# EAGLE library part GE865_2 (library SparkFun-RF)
Telit quad cell module (CEL-09720)

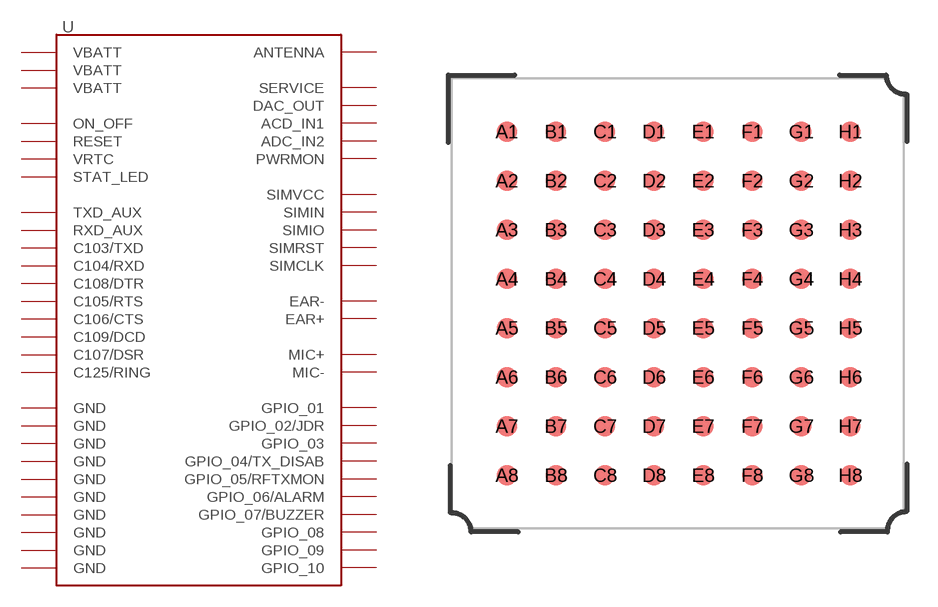
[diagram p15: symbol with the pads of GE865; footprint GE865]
Designator prefix -

## GE865_2  [GE865]
A1  C105/RTS
A2  C106/CTS
A3  C103/TXD
A4  C104/RXD
A5  SIMCLK
A6  SIMIO
A7  SIMVCC
A8  SIMRST
B1  ON_OFF
B2  C107/DSR
B3  C108/DTR
B4  C125/RING
B5  C109/DCD
B7  SIMIN
B8  MIC+
C1  RESET
C2  GND
C7  GND
C8  MIC-
D1  TXD_AUX
D2  GPIO_02/JDR
D3  GPIO_01
D4  GPIO_08
D8  EAR+
E1  RXD_AUX
E2  PWRMON
E3  GPIO_10
E4  GPIO_03
E5  GND
E7  GND
E8  EAR-
F1  VBATT
F2  VBATT
F3  VBATT
F4  GPIO_09
F5  ACD_IN1
F6  ADC_IN2
G1  GND
G2  GPIO_05/RFTXMON
G3  GND
G4  GND
G5  GND
G6  GPIO_07/BUZZER
G7  DAC_OUT
G8  STAT_LED
H1  SERVICE
H2  VRTC
H3  GND
H5  ANTENNA
H6  GND
H7  GPIO_04/TX_DISAB
H8  GPIO_06/ALARM

## Footprint GE865 (pad centres in mm)
smd 1 x 1: A1 -8.4,8.4; A2 -8.4,6; A3 -8.4,3.6; A4 -8.4,1.2; A5 -8.4,-1.2; A6 -8.4,-3.6; A7 -8.4,-6; A8 -8.4,-8.4; B1 -6,8.4; B2 -6,6; B3 -6,3.6; B4 -6,1.2; B5 -6,-1.2; B6 -6,-3.6; B7 -6,-6; B8 -6,-8.4; C1 -3.6,8.4; C2 -3.6,6; C3 -3.6,3.6; C4 -3.6,1.2; C5 -3.6,-1.2; C6 -3.6,-3.6; C7 -3.6,-6; C8 -3.6,-8.4; D1 -1.2,8.4; D2 -1.2,6; D3 -1.2,3.6; D4 -1.2,1.2; D5 -1.2,-1.2; D6 -1.2,-3.6; D7 -1.2,-6; D8 -1.2,-8.4; E1 1.2,8.4; E2 1.2,6; E3 1.2,3.6; E4 1.2,1.2; E5 1.2,-1.2; E6 1.2,-3.6; E7 1.2,-6; E8 1.2,-8.4; F1 3.6,8.4; F2 3.6,6; F3 3.6,3.6; F4 3.6,1.2; F5 3.6,-1.2; F6 3.6,-3.6; F7 3.6,-6; F8 3.6,-8.4; G1 6,8.4; G2 6,6; G3 6,3.6; G4 6,1.2; G5 6,-1.2; G6 6,-3.6; G7 6,-6; G8 6,-8.4; H1 8.4,8.4; H2 8.4,6; H3 8.4,3.6; H4 8.4,1.2; H5 8.4,-1.2; H6 8.4,-3.6; H7 8.4,-6; H8 8.4,-8.4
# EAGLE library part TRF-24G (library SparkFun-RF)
2.4GHz wireless module

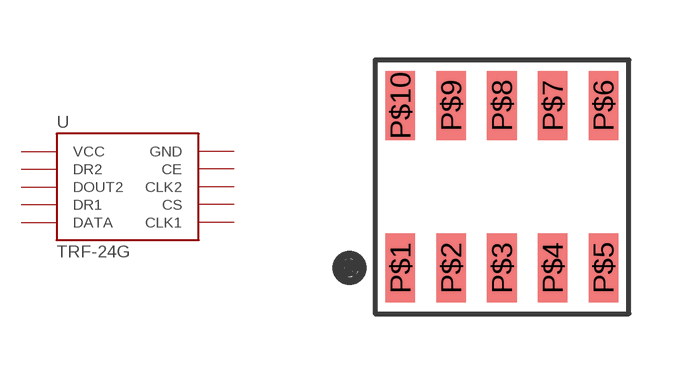
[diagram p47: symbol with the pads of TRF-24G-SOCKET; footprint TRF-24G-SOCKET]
Designator prefix -

## TRF-24G  [TRF-24G-SOCKET]
P$1  VCC
P$2  DR2
P$3  DOUT2
P$4  DR1
P$5  DATA
P$6  CLK1
P$7  CS
P$8  CLK2
P$9  CE
P$10  GND

## Footprint TRF-24G-SOCKET (pad centres in mm)
smd 0.74 x 1.727: P$1 0,0; P$2 1.27,0; P$3 2.54,0; P$4 3.81,0; P$5 5.08,0; P$6 5.08,4.064; P$7 3.81,4.064; P$8 2.54,4.064; P$9 1.27,4.064; P$10 0,4.064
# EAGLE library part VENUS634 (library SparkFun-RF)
Venus634 from SkyTraq

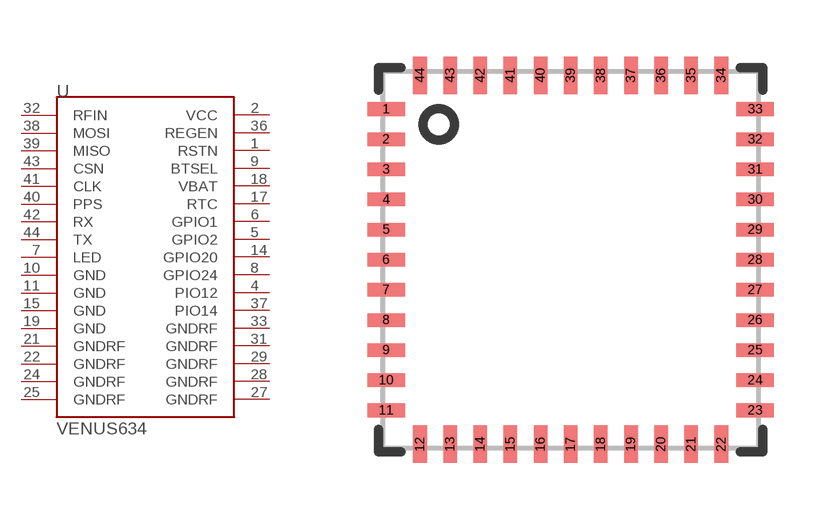
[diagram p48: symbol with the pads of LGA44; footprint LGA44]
Designator prefix -

## VENUS634SMD (PROD_ID: IC-12645)  [LGA44]
1  RSTN
2  VCC
4  PIO12
5  GPIO2
6  GPIO1
7  LED
8  GPIO24
9  BTSEL
10  GND
11  GND
14  GPIO20
15  GND
17  RTC
18  VBAT
19  GND
21  GNDRF
22  GNDRF
24  GNDRF
25  GNDRF
27  GNDRF
28  GNDRF
29  GNDRF
31  GNDRF
32  RFIN
33  GNDRF
36  REGEN
37  PIO14
38  MOSI
39  MISO
40  PPS
41  CLK
42  RX
43  CSN
44  TX

## Footprint LGA44 (pad centres in mm)
LGA44 - Used for Venus GPS
smd 1 x 0.36: 1 -4.9,4; 2 -4.9,3.2; 3 -4.9,2.4; 4 -4.9,1.6; 5 -4.9,0.8; 6 -4.9,0; 7 -4.9,-0.8; 8 -4.9,-1.6; 9 -4.9,-2.4; 10 -4.9,-3.2; 11 -4.9,-4; 23 4.9,-4; 24 4.9,-3.2; 25 4.9,-2.4; 26 4.9,-1.6; 27 4.9,-0.8; 28 4.9,0; 29 4.9,0.8; 30 4.9,1.6; 31 4.9,2.4; 32 4.9,3.2; 33 4.9,4
smd 0.36 x 1: 12 -4,-4.9; 13 -3.2,-4.9; 14 -2.4,-4.9; 15 -1.6,-4.9; 16 -0.8,-4.9; 17 0,-4.9; 18 0.8,-4.9; 19 1.6,-4.9; 20 2.4,-4.9; 21 3.2,-4.9; 22 4,-4.9; 34 4,4.9; 35 3.2,4.9; 36 2.4,4.9; 37 1.6,4.9; 38 0.8,4.9; 39 0,4.9; 40 -0.8,4.9; 41 -1.6,4.9; 42 -2.4,4.9; 43 -3.2,4.9; 44 -4,4.9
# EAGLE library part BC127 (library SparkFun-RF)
Blue Creations BC127 BLE module Hyper-competent Bluetooth 4.0 module, with: - Pre-4.0 support - 4 Cap sense inputs - 1 Analog input - 8 GPIO - 3 Open-drain LED drivers - Onboard battery charge circuitry - SPP/UART support - PCM Audio support - SPI port - Built-in USB - All kinds of other crazy crap

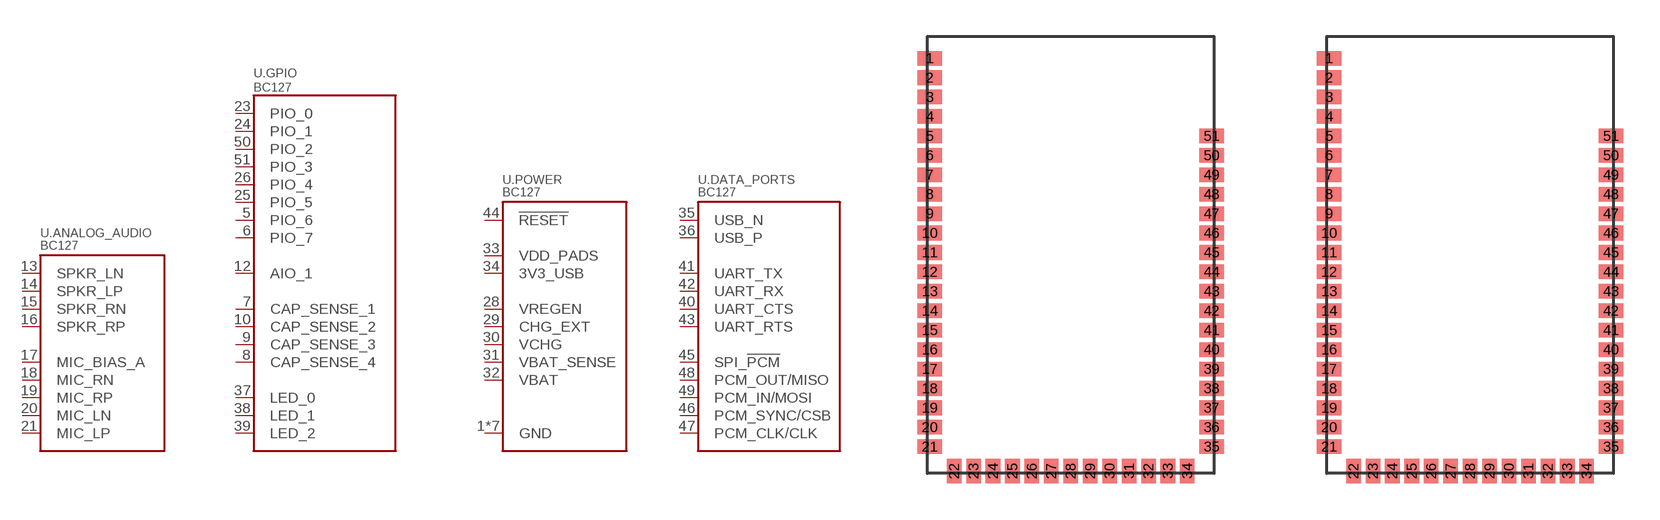
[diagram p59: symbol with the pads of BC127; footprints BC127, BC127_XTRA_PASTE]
Designator prefix U; gates .ANALOG_AUDIO=BC127_ANALOG_AUDIO .GPIO=BC127_GPIO .POWER=BC127_POWER .DATA_PORTS=BC127_DATA_PORTS

## BC127 (VALUE: BC127)  [BC127]
1  .POWER:GND
2  .POWER:GND
3  .POWER:GND
4  .POWER:GND
5  .GPIO:PIO_6
6  .GPIO:PIO_7
7  .GPIO:CAP_SENSE_1
8  .GPIO:CAP_SENSE_4
9  .GPIO:CAP_SENSE_3
10  .GPIO:CAP_SENSE_2
11  .POWER:GND
12  .GPIO:AIO_1
13  .ANALOG_AUDIO:SPKR_LN
14  .ANALOG_AUDIO:SPKR_LP
15  .ANALOG_AUDIO:SPKR_RN
16  .ANALOG_AUDIO:SPKR_RP
17  .ANALOG_AUDIO:MIC_BIAS_A
18  .ANALOG_AUDIO:MIC_RN
19  .ANALOG_AUDIO:MIC_RP
20  .ANALOG_AUDIO:MIC_LN
21  .ANALOG_AUDIO:MIC_LP
22  .POWER:GND
23  .GPIO:PIO_0
24  .GPIO:PIO_1
25  .GPIO:PIO_5
26  .GPIO:PIO_4
27  .POWER:GND
28  .POWER:VREGEN
29  .POWER:CHG_EXT
30  .POWER:VCHG
31  .POWER:VBAT_SENSE
32  .POWER:VBAT
33  .POWER:VDD_PADS
34  .POWER:3V3_USB
35  .DATA_PORTS:USB_N
36  .DATA_PORTS:USB_P
37  .GPIO:LED_0
38  .GPIO:LED_1
39  .GPIO:LED_2
40  .DATA_PORTS:UART_CTS
41  .DATA_PORTS:UART_TX
42  .DATA_PORTS:UART_RX
43  .DATA_PORTS:UART_RTS
44  .POWER:!RESET
45  .DATA_PORTS:SPI_!PCM
46  .DATA_PORTS:PCM_SYNC/CSB
47  .DATA_PORTS:PCM_CLK/CLK
48  .DATA_PORTS:PCM_OUT/MISO
49  .DATA_PORTS:PCM_IN/MOSI
50  .GPIO:PIO_2
51  .GPIO:PIO_3

## BC127EXTRA_PASTE  [BC127_XTRA_PASTE]
Pads as for BC127

## Footprint BC127 (pad centres in mm)
smd 1 x 0.6: 1 -5.8,8.1; 2 -5.8,7.3; 3 -5.8,6.5; 4 -5.8,5.7; 5 -5.8,4.9; 6 -5.8,4.1; 7 -5.8,3.3; 8 -5.8,2.5; 9 -5.8,1.7; 10 -5.8,0.9; 11 -5.8,0.1; 12 -5.8,-0.7; 13 -5.8,-1.5; 14 -5.8,-2.3; 15 -5.8,-3.1; 16 -5.8,-3.9; 17 -5.8,-4.7; 18 -5.8,-5.5; 19 -5.8,-6.3; 20 -5.8,-7.1; 21 -5.8,-7.9; 35 5.8,-7.9; 36 5.8,-7.1; 37 5.8,-6.3; 38 5.8,-5.5; 39 5.8,-4.7; 40 5.8,-3.9; 41 5.8,-3.1; 42 5.8,-2.3; 43 5.8,-1.5; 44 5.8,-0.7; 45 5.8,0.1; 46 5.8,0.9; 47 5.8,1.7; 48 5.8,2.5; 49 5.8,3.3; 50 5.8,4.1; 51 5.8,4.9
smd 0.6 x 1: 22 -4.8,-8.9; 23 -4,-8.9; 24 -3.2,-8.9; 25 -2.4,-8.9; 26 -1.6,-8.9; 27 -0.8,-8.9; 28 0,-8.9; 29 0.8,-8.9; 30 1.6,-8.9; 31 2.4,-8.9; 32 3.2,-8.9; 33 4,-8.9; 34 4.8,-8.9

## Footprint BC127_XTRA_PASTE (pad centres in mm)
smd 1 x 0.6: 1 -5.8,8.1; 2 -5.8,7.3; 3 -5.8,6.5; 4 -5.8,5.7; 5 -5.8,4.9; 6 -5.8,4.1; 7 -5.8,3.3; 8 -5.8,2.5; 9 -5.8,1.7; 10 -5.8,0.9; 11 -5.8,0.1; 12 -5.8,-0.7; 13 -5.8,-1.5; 14 -5.8,-2.3; 15 -5.8,-3.1; 16 -5.8,-3.9; 17 -5.8,-4.7; 18 -5.8,-5.5; 19 -5.8,-6.3; 20 -5.8,-7.1; 21 -5.8,-7.9; 35 5.8,-7.9; 36 5.8,-7.1; 37 5.8,-6.3; 38 5.8,-5.5; 39 5.8,-4.7; 40 5.8,-3.9; 41 5.8,-3.1; 42 5.8,-2.3; 43 5.8,-1.5; 44 5.8,-0.7; 45 5.8,0.1; 46 5.8,0.9; 47 5.8,1.7; 48 5.8,2.5; 49 5.8,3.3; 50 5.8,4.1; 51 5.8,4.9
smd 0.6 x 1: 22 -4.8,-8.9; 23 -4,-8.9; 24 -3.2,-8.9; 25 -2.4,-8.9; 26 -1.6,-8.9; 27 -0.8,-8.9; 28 0,-8.9; 29 0.8,-8.9; 30 1.6,-8.9; 31 2.4,-8.9; 32 3.2,-8.9; 33 4,-8.9; 34 4.8,-8.9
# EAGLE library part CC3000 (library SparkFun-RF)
TI CC3000 WiFi Module

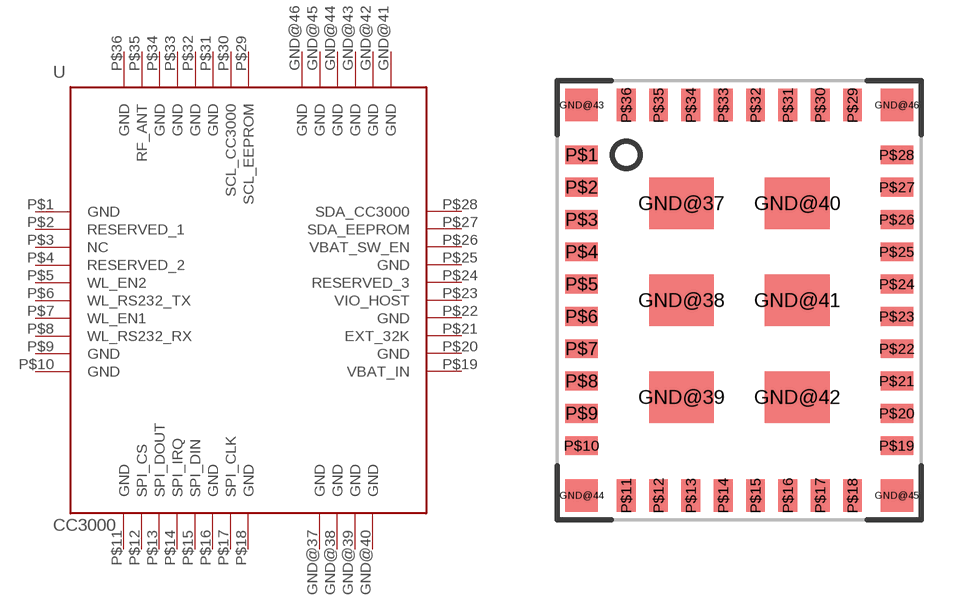
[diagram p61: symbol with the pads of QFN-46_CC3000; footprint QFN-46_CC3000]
Designator prefix -

## CC3000  [QFN-46_CC3000]
GND@37  GND
GND@38  GND
GND@39  GND
GND@40  GND
GND@41  GND
GND@42  GND
GND@43  GND
GND@44  GND
GND@45  GND
GND@46  GND
P$1  GND
P$2  RESERVED_1
P$3  NC
P$4  RESERVED_2
P$5  WL_EN2
P$6  WL_RS232_TX
P$7  WL_EN1
P$8  WL_RS232_RX
P$9  GND
P$10  GND
P$11  GND
P$12  SPI_CS
P$13  SPI_DOUT
P$14  SPI_IRQ
P$15  SPI_DIN
P$16  GND
P$17  SPI_CLK
P$18  GND
P$19  VBAT_IN
P$20  GND
P$21  EXT_32K
P$22  GND
P$23  VIO_HOST
P$24  RESERVED_3
P$25  GND
P$26  VBAT_SW_EN
P$27  SDA_EEPROM
P$28  SDA_CC3000
P$29  SCL_EEPROM
P$30  SCL_CC3000
P$31  GND
P$32  GND
P$33  GND
P$34  GND
P$35  RF_ANT
P$36  GND

## Footprint QFN-46_CC3000 (pad centres in mm)
smd 2.4 x 1.9: GND@37 -2.15,3.6; GND@38 -2.15,0; GND@39 -2.15,-3.6; GND@40 2.15,3.6; GND@41 2.15,0; GND@42 2.15,-3.6
smd 1.2 x 1.2: GND@43 -5.85,7.25; GND@44 -5.85,-7.25; GND@45 5.85,-7.25; GND@46 5.85,7.25
smd 1.2 x 0.7: P$1 -5.85,5.4; P$2 -5.85,4.2; P$3 -5.85,3; P$4 -5.85,1.8; P$5 -5.85,0.6; P$6 -5.85,-0.6; P$7 -5.85,-1.8; P$8 -5.85,-3; P$9 -5.85,-4.2; P$10 -5.85,-5.4; P$19 5.85,-5.4; P$20 5.85,-4.2; P$21 5.85,-3; P$22 5.85,-1.8; P$23 5.85,-0.6; P$24 5.85,0.6; P$25 5.85,1.8; P$26 5.85,3; P$27 5.85,4.2; P$28 5.85,5.4
smd 0.7 x 1.2: P$11 -4.2,-7.25; P$12 -3,-7.25; P$13 -1.8,-7.25; P$14 -0.6,-7.25; P$15 0.6,-7.25; P$16 1.8,-7.25; P$17 3,-7.25; P$18 4.2,-7.25; P$29 4.2,7.25; P$30 3,7.25; P$31 1.8,7.25; P$32 0.6,7.25; P$33 -0.6,7.25; P$34 -1.8,7.25; P$35 -3,7.25; P$36 -4.2,7.25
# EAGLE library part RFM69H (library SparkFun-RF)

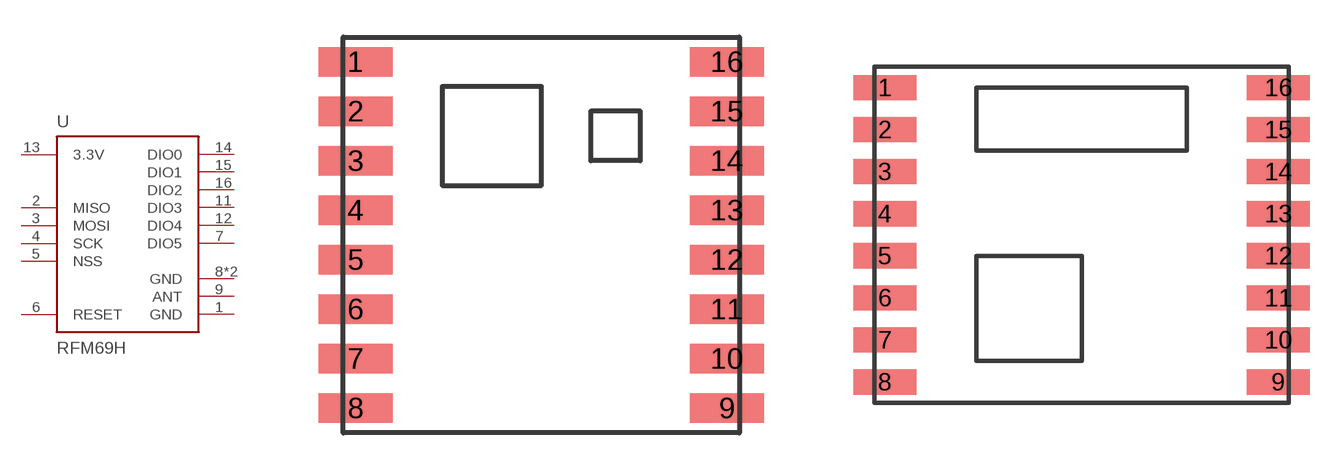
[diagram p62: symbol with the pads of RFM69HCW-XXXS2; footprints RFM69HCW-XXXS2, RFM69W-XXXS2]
Designator prefix U

## RFM69HCW (PROD_ID: IC-11997, IC-12053)  [RFM69HCW-XXXS2]
1  GND  pwr
2  MISO
3  MOSI  in
4  SCK  in
5  NSS  in
6  RESET  in
7  DIO5
8  GND  pwr
9  ANT  pas
10  GND  pwr
11  DIO3
12  DIO4
13  3.3V  pwr
14  DIO0
15  DIO1
16  DIO2

## RFM69HW  [RFM69W-XXXS2]
1  RESET  in
2  DIO0
3  DIO1
4  DIO2
5  DIO3
6  DIO4
7  DIO5
8  3.3V  pwr
9  GND  pwr
10  ANT  pas
11  GND  pwr
12  SCK  in
13  MISO
14  MOSI  in
15  NSS  in

## Footprint RFM69HCW-XXXS2 (pad centres in mm)
smd 3 x 1.2: 1 -7.5,7; 2 -7.5,5; 3 -7.5,3; 4 -7.5,1; 5 -7.5,-1; 6 -7.5,-3; 7 -7.5,-5; 8 -7.5,-7; 9 7.5,-7; 10 7.5,-5; 11 7.5,-3; 12 7.5,-1; 13 7.5,1; 14 7.5,3; 15 7.5,5; 16 7.5,7

## Footprint RFM69W-XXXS2 (pad centres in mm)
smd 3 x 1.2: 1 -9.35,7; 2 -9.35,5; 3 -9.35,3; 4 -9.35,1; 5 -9.35,-1; 6 -9.35,-3; 7 -9.35,-5; 8 -9.35,-7; 9 9.35,-7; 10 9.35,-5; 11 9.35,-3; 12 9.35,-1; 13 9.35,1; 14 9.35,3; 15 9.35,5; 16 9.35,7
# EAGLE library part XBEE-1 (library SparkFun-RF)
Xbee module footprints

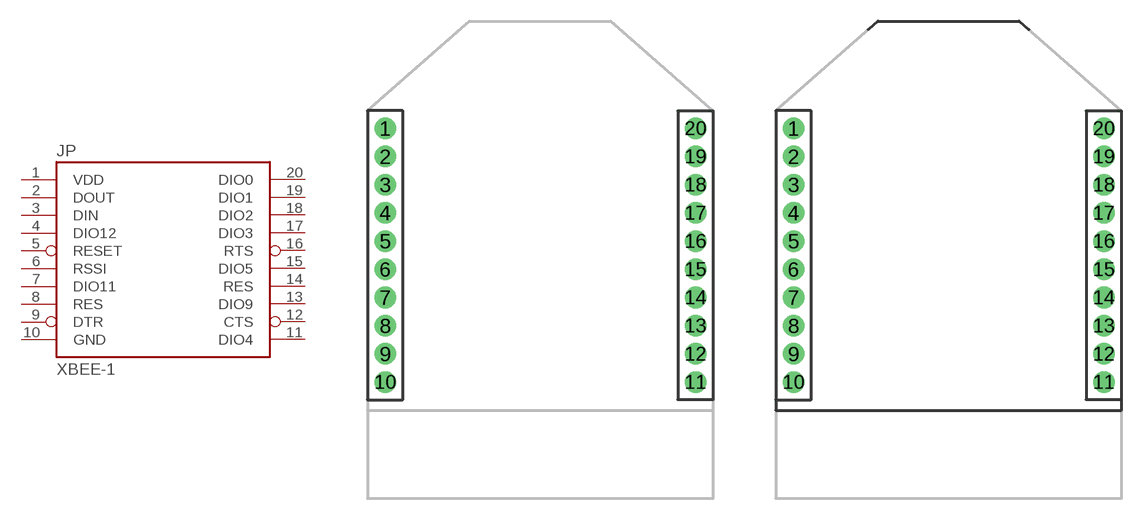
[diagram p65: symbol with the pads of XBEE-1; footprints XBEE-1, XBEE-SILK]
Designator prefix JP

## XBEE-1B1  [XBEE-1]
1  VDD  pwr
2  DOUT  out
3  DIN  in
4  DIO12
5  RESET  in
6  RSSI
7  DIO11
8  RES
9  DTR
10  GND  pwr
11  DIO4
12  CTS  out
13  DIO9
14  RES
15  DIO5
16  RTS  in
17  DIO3
18  DIO2
19  DIO1
20  DIO0

## XBEE-1B2  [XBEE-SILK]
Pads as for XBEE-1

## XBEE-1B3 (PROD_ID: CONN-09042)  [XBEE-SMD]
Pads as for XBEE-1

## XBEE-1LONGPAD  [XBEE-LONGPAD]
Pads as for XBEE-1

## XBEE-1XBEE-1_LOCK  [XBEE-1_LOCK]
Pads as for XBEE-1

## Footprint XBEE-1 (pad centres in mm)
drill 0.8 pad 1.524: 1 -11,20; 2 -11,18; 3 -11,16; 4 -11,14; 5 -11,12; 6 -11,10; 7 -11,8; 8 -11,6; 9 -11,4; 10 -11,2; 11 11,2; 12 11,4; 13 11,6; 14 11,8; 15 11,10; 16 11,12; 17 11,14; 18 11,16; 19 11,18; 20 11,20

## Footprint XBEE-SILK (pad centres in mm)
drill 0.8 pad 1.524: 1 -11,20; 2 -11,18; 3 -11,16; 4 -11,14; 5 -11,12; 6 -11,10; 7 -11,8; 8 -11,6; 9 -11,4; 10 -11,2; 11 11,2; 12 11,4; 13 11,6; 14 11,8; 15 11,10; 16 11,12; 17 11,14; 18 11,16; 19 11,18; 20 11,20

## Footprint XBEE-SMD (pad centres in mm)
smd 1.7 x 0.85: 1 -12.5,20; 2 -9.5,18; 3 -12.5,16; 4 -9.5,14; 5 -12.5,12; 6 -9.5,10; 7 -12.5,8; 8 -9.5,6; 9 -12.5,4; 10 -9.5,2; 11 12.5,2; 12 9.5,4; 13 12.5,6; 14 9.5,8; 15 12.5,10; 16 9.5,12; 17 12.5,14; 18 9.5,16; 19 12.5,18; 20 9.5,20

## Footprint XBEE-LONGPAD (pad centres in mm)
drill 0.8 pad 1.206 long: 1 -11,20; 2 -11,18; 3 -11,16; 4 -11,14; 5 -11,12; 6 -11,10; 7 -11,8; 8 -11,6; 9 -11,4; 10 -11,2; 11 11,2; 12 11,4; 13 11,6; 14 11,8; 15 11,10; 16 11,12; 17 11,14; 18 11,16; 19 11,18; 20 11,20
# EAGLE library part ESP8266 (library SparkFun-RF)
Espressif ESP8266 WiFi Smart Connectivity Platform.

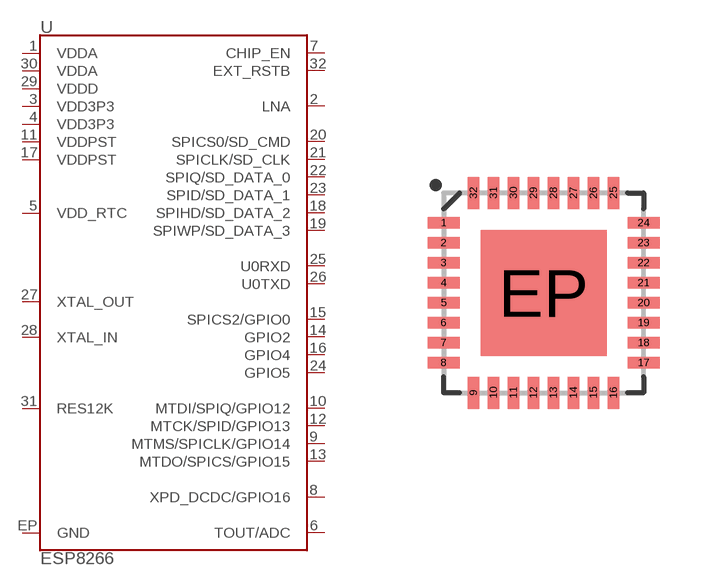
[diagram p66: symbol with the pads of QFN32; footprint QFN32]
Designator prefix U

## ESP8266 (PROD_ID: IC-12452)  [QFN32]
1  VDDA
2  LNA
3  VDD3P3
4  VDD3P3
5  VDD_RTC
6  TOUT/ADC
7  CHIP_EN
8  XPD_DCDC/GPIO16
9  MTMS/SPICLK/GPIO14
10  MTDI/SPIQ/GPIO12
11  VDDPST
12  MTCK/SPID/GPIO13
13  MTDO/SPICS/GPIO15
14  GPIO2
15  SPICS2/GPIO0
16  GPIO4
17  VDDPST
18  SPIHD/SD_DATA_2
19  SPIWP/SD_DATA_3
20  SPICS0/SD_CMD
21  SPICLK/SD_CLK
22  SPIQ/SD_DATA_0
23  SPID/SD_DATA_1
24  GPIO5
25  U0RXD
26  U0TXD
27  XTAL_OUT
28  XTAL_IN
29  VDDD
30  VDDA
31  RES12K
32  EXT_RSTB
EP  GND

## Footprint QFN32 (pad centres in mm)
32-pin QFN package Used by ESP8266.
smd 0.8 x 0.285: 1 -2.5,1.75; 2 -2.5,1.25; 3 -2.5,0.75; 4 -2.5,0.25; 5 -2.5,-0.25; 6 -2.5,-0.75; 7 -2.5,-1.25; 8 -2.5,-1.75; 17 2.5,-1.75; 18 2.5,-1.25; 19 2.5,-0.75; 20 2.5,-0.25; 21 2.5,0.25; 22 2.5,0.75; 23 2.5,1.25; 24 2.5,1.75
smd 0.285 x 0.8: 9 -1.75,-2.5; 10 -1.25,-2.5; 11 -0.75,-2.5; 12 -0.25,-2.5; 13 0.25,-2.5; 14 0.75,-2.5; 15 1.25,-2.5; 16 1.75,-2.5; 25 1.75,2.5; 26 1.25,2.5; 27 0.75,2.5; 28 0.25,2.5; 29 -0.25,2.5; 30 -0.75,2.5; 31 -1.25,2.5; 32 -1.75,2.5
smd 3.15 x 3.15: EP 0,0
